VERSION 5.7 ;
  NOWIREEXTENSIONATPIN ON ;
  DIVIDERCHAR "/" ;
  BUSBITCHARS "[]" ;
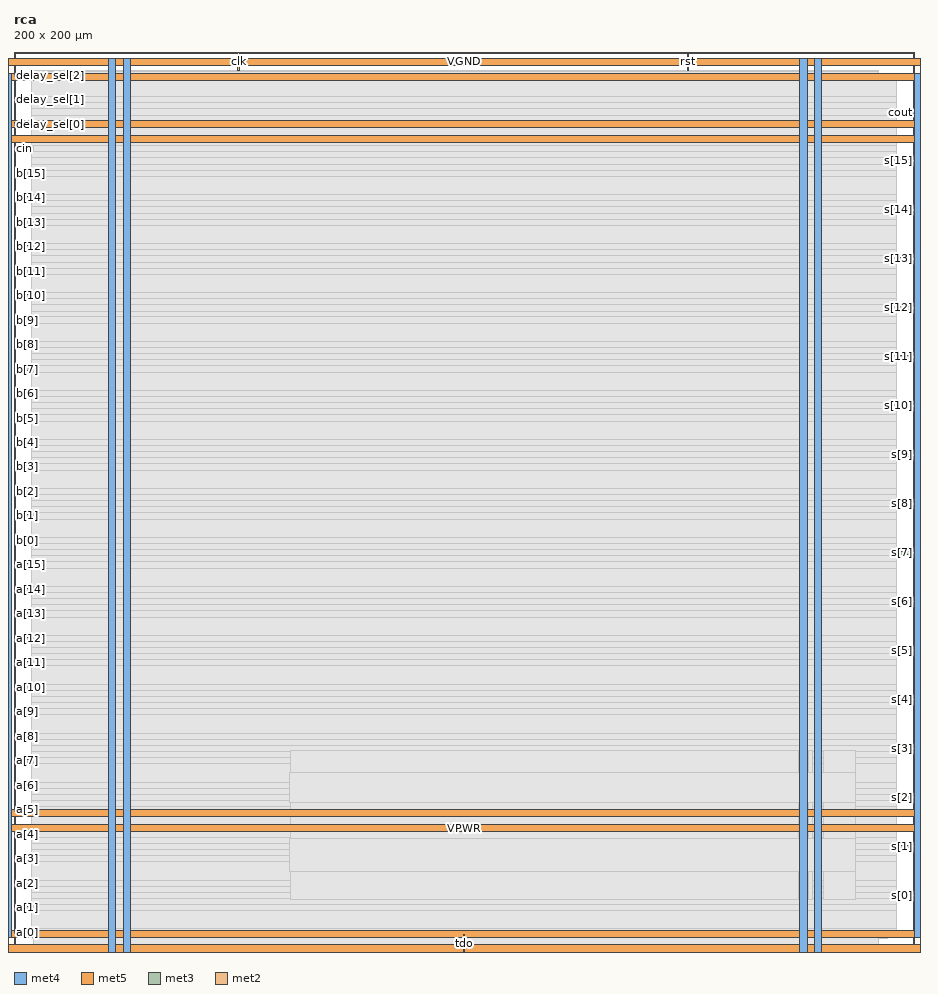
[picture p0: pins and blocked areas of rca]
MACRO rca
  CLASS BLOCK ;
  FOREIGN rca ;
  ORIGIN 0.000 0.000 ;
  SIZE 200.000 BY 200.000 ;
  PIN VGND
    DIRECTION INOUT ;
    USE GROUND ;
    PORT
      LAYER met4 ;
        RECT -5.380 -0.020 -3.780 198.580 ;
    END
    PORT
      LAYER met5 ;
        RECT -5.380 -0.020 205.020 1.580 ;
    END
    PORT
      LAYER met5 ;
        RECT -5.380 196.980 205.020 198.580 ;
    END
    PORT
      LAYER met4 ;
        RECT 203.420 -0.020 205.020 198.580 ;
    END
    PORT
      LAYER met4 ;
        RECT 24.340 -0.020 25.940 198.580 ;
    END
    PORT
      LAYER met4 ;
        RECT 177.940 -0.020 179.540 198.580 ;
    END
    PORT
      LAYER met5 ;
        RECT -5.380 30.030 205.020 31.630 ;
    END
    PORT
      LAYER met5 ;
        RECT -5.380 183.210 205.020 184.810 ;
    END
  END VGND
  PIN VPWR
    DIRECTION INOUT ;
    USE POWER ;
    PORT
      LAYER met4 ;
        RECT -2.080 3.280 -0.480 195.280 ;
    END
    PORT
      LAYER met5 ;
        RECT -2.080 3.280 201.720 4.880 ;
    END
    PORT
      LAYER met5 ;
        RECT -2.080 193.680 201.720 195.280 ;
    END
    PORT
      LAYER met4 ;
        RECT 200.120 3.280 201.720 195.280 ;
    END
    PORT
      LAYER met4 ;
        RECT 21.040 -0.020 22.640 198.580 ;
    END
    PORT
      LAYER met4 ;
        RECT 174.640 -0.020 176.240 198.580 ;
    END
    PORT
      LAYER met5 ;
        RECT -5.380 26.730 205.020 28.330 ;
    END
    PORT
      LAYER met5 ;
        RECT -5.380 179.910 205.020 181.510 ;
    END
  END VPWR
  PIN a[0]
    DIRECTION INPUT ;
    USE SIGNAL ;
    ANTENNAGATEAREA 0.196500 ;
    PORT
      LAYER met3 ;
        RECT 0.000 4.120 4.000 4.720 ;
    END
  END a[0]
  PIN a[10]
    DIRECTION INPUT ;
    USE SIGNAL ;
    ANTENNAGATEAREA 0.196500 ;
    PORT
      LAYER met3 ;
        RECT 0.000 58.520 4.000 59.120 ;
    END
  END a[10]
  PIN a[11]
    DIRECTION INPUT ;
    USE SIGNAL ;
    ANTENNAGATEAREA 0.196500 ;
    PORT
      LAYER met3 ;
        RECT 0.000 63.960 4.000 64.560 ;
    END
  END a[11]
  PIN a[12]
    DIRECTION INPUT ;
    USE SIGNAL ;
    ANTENNAGATEAREA 0.196500 ;
    PORT
      LAYER met3 ;
        RECT 0.000 69.400 4.000 70.000 ;
    END
  END a[12]
  PIN a[13]
    DIRECTION INPUT ;
    USE SIGNAL ;
    ANTENNAGATEAREA 0.196500 ;
    PORT
      LAYER met3 ;
        RECT 0.000 74.840 4.000 75.440 ;
    END
  END a[13]
  PIN a[14]
    DIRECTION INPUT ;
    USE SIGNAL ;
    ANTENNAGATEAREA 0.196500 ;
    PORT
      LAYER met3 ;
        RECT 0.000 80.280 4.000 80.880 ;
    END
  END a[14]
  PIN a[15]
    DIRECTION INPUT ;
    USE SIGNAL ;
    ANTENNAGATEAREA 0.196500 ;
    PORT
      LAYER met3 ;
        RECT 0.000 85.720 4.000 86.320 ;
    END
  END a[15]
  PIN a[1]
    DIRECTION INPUT ;
    USE SIGNAL ;
    ANTENNAGATEAREA 0.196500 ;
    PORT
      LAYER met3 ;
        RECT 0.000 9.560 4.000 10.160 ;
    END
  END a[1]
  PIN a[2]
    DIRECTION INPUT ;
    USE SIGNAL ;
    ANTENNAGATEAREA 0.196500 ;
    PORT
      LAYER met3 ;
        RECT 0.000 15.000 4.000 15.600 ;
    END
  END a[2]
  PIN a[3]
    DIRECTION INPUT ;
    USE SIGNAL ;
    ANTENNAGATEAREA 0.196500 ;
    PORT
      LAYER met3 ;
        RECT 0.000 20.440 4.000 21.040 ;
    END
  END a[3]
  PIN a[4]
    DIRECTION INPUT ;
    USE SIGNAL ;
    ANTENNAGATEAREA 0.196500 ;
    PORT
      LAYER met3 ;
        RECT 0.000 25.880 4.000 26.480 ;
    END
  END a[4]
  PIN a[5]
    DIRECTION INPUT ;
    USE SIGNAL ;
    ANTENNAGATEAREA 0.196500 ;
    PORT
      LAYER met3 ;
        RECT 0.000 31.320 4.000 31.920 ;
    END
  END a[5]
  PIN a[6]
    DIRECTION INPUT ;
    USE SIGNAL ;
    ANTENNAGATEAREA 0.196500 ;
    PORT
      LAYER met3 ;
        RECT 0.000 36.760 4.000 37.360 ;
    END
  END a[6]
  PIN a[7]
    DIRECTION INPUT ;
    USE SIGNAL ;
    ANTENNAGATEAREA 0.196500 ;
    PORT
      LAYER met3 ;
        RECT 0.000 42.200 4.000 42.800 ;
    END
  END a[7]
  PIN a[8]
    DIRECTION INPUT ;
    USE SIGNAL ;
    ANTENNAGATEAREA 0.196500 ;
    PORT
      LAYER met3 ;
        RECT 0.000 47.640 4.000 48.240 ;
    END
  END a[8]
  PIN a[9]
    DIRECTION INPUT ;
    USE SIGNAL ;
    ANTENNAGATEAREA 0.196500 ;
    PORT
      LAYER met3 ;
        RECT 0.000 53.080 4.000 53.680 ;
    END
  END a[9]
  PIN b[0]
    DIRECTION INPUT ;
    USE SIGNAL ;
    ANTENNAGATEAREA 0.196500 ;
    PORT
      LAYER met3 ;
        RECT 0.000 91.160 4.000 91.760 ;
    END
  END b[0]
  PIN b[10]
    DIRECTION INPUT ;
    USE SIGNAL ;
    ANTENNAGATEAREA 0.196500 ;
    PORT
      LAYER met3 ;
        RECT 0.000 145.560 4.000 146.160 ;
    END
  END b[10]
  PIN b[11]
    DIRECTION INPUT ;
    USE SIGNAL ;
    ANTENNAGATEAREA 0.196500 ;
    PORT
      LAYER met3 ;
        RECT 0.000 151.000 4.000 151.600 ;
    END
  END b[11]
  PIN b[12]
    DIRECTION INPUT ;
    USE SIGNAL ;
    ANTENNAGATEAREA 0.196500 ;
    PORT
      LAYER met3 ;
        RECT 0.000 156.440 4.000 157.040 ;
    END
  END b[12]
  PIN b[13]
    DIRECTION INPUT ;
    USE SIGNAL ;
    ANTENNAGATEAREA 0.196500 ;
    PORT
      LAYER met3 ;
        RECT 0.000 161.880 4.000 162.480 ;
    END
  END b[13]
  PIN b[14]
    DIRECTION INPUT ;
    USE SIGNAL ;
    ANTENNAGATEAREA 0.196500 ;
    PORT
      LAYER met3 ;
        RECT 0.000 167.320 4.000 167.920 ;
    END
  END b[14]
  PIN b[15]
    DIRECTION INPUT ;
    USE SIGNAL ;
    ANTENNAGATEAREA 0.196500 ;
    PORT
      LAYER met3 ;
        RECT 0.000 172.760 4.000 173.360 ;
    END
  END b[15]
  PIN b[1]
    DIRECTION INPUT ;
    USE SIGNAL ;
    ANTENNAGATEAREA 0.196500 ;
    PORT
      LAYER met3 ;
        RECT 0.000 96.600 4.000 97.200 ;
    END
  END b[1]
  PIN b[2]
    DIRECTION INPUT ;
    USE SIGNAL ;
    ANTENNAGATEAREA 0.196500 ;
    PORT
      LAYER met3 ;
        RECT 0.000 102.040 4.000 102.640 ;
    END
  END b[2]
  PIN b[3]
    DIRECTION INPUT ;
    USE SIGNAL ;
    ANTENNAGATEAREA 0.196500 ;
    PORT
      LAYER met3 ;
        RECT 0.000 107.480 4.000 108.080 ;
    END
  END b[3]
  PIN b[4]
    DIRECTION INPUT ;
    USE SIGNAL ;
    ANTENNAGATEAREA 0.196500 ;
    PORT
      LAYER met3 ;
        RECT 0.000 112.920 4.000 113.520 ;
    END
  END b[4]
  PIN b[5]
    DIRECTION INPUT ;
    USE SIGNAL ;
    ANTENNAGATEAREA 0.196500 ;
    PORT
      LAYER met3 ;
        RECT 0.000 118.360 4.000 118.960 ;
    END
  END b[5]
  PIN b[6]
    DIRECTION INPUT ;
    USE SIGNAL ;
    ANTENNAGATEAREA 0.196500 ;
    PORT
      LAYER met3 ;
        RECT 0.000 123.800 4.000 124.400 ;
    END
  END b[6]
  PIN b[7]
    DIRECTION INPUT ;
    USE SIGNAL ;
    ANTENNAGATEAREA 0.196500 ;
    PORT
      LAYER met3 ;
        RECT 0.000 129.240 4.000 129.840 ;
    END
  END b[7]
  PIN b[8]
    DIRECTION INPUT ;
    USE SIGNAL ;
    ANTENNAGATEAREA 0.196500 ;
    PORT
      LAYER met3 ;
        RECT 0.000 134.680 4.000 135.280 ;
    END
  END b[8]
  PIN b[9]
    DIRECTION INPUT ;
    USE SIGNAL ;
    ANTENNAGATEAREA 0.196500 ;
    PORT
      LAYER met3 ;
        RECT 0.000 140.120 4.000 140.720 ;
    END
  END b[9]
  PIN cin
    DIRECTION INPUT ;
    USE SIGNAL ;
    ANTENNAGATEAREA 0.196500 ;
    PORT
      LAYER met3 ;
        RECT 0.000 178.200 4.000 178.800 ;
    END
  END cin
  PIN clk
    DIRECTION INPUT ;
    USE SIGNAL ;
    ANTENNAGATEAREA 1.704000 ;
    PORT
      LAYER met2 ;
        RECT 49.770 196.000 50.050 200.000 ;
    END
  END clk
  PIN cout
    DIRECTION OUTPUT ;
    USE SIGNAL ;
    ANTENNADIFFAREA 0.445500 ;
    PORT
      LAYER met3 ;
        RECT 196.000 186.360 200.000 186.960 ;
    END
  END cout
  PIN delay_sel[0]
    DIRECTION INPUT ;
    USE SIGNAL ;
    ANTENNAGATEAREA 0.159000 ;
    PORT
      LAYER met3 ;
        RECT 0.000 183.640 4.000 184.240 ;
    END
  END delay_sel[0]
  PIN delay_sel[1]
    DIRECTION INPUT ;
    USE SIGNAL ;
    ANTENNAGATEAREA 0.159000 ;
    PORT
      LAYER met3 ;
        RECT 0.000 189.080 4.000 189.680 ;
    END
  END delay_sel[1]
  PIN delay_sel[2]
    DIRECTION INPUT ;
    USE SIGNAL ;
    ANTENNAGATEAREA 0.213000 ;
    PORT
      LAYER met3 ;
        RECT 0.000 194.520 4.000 195.120 ;
    END
  END delay_sel[2]
  PIN rst
    DIRECTION INPUT ;
    USE SIGNAL ;
    ANTENNAGATEAREA 0.196500 ;
    PORT
      LAYER met2 ;
        RECT 149.590 196.000 149.870 200.000 ;
    END
  END rst
  PIN s[0]
    DIRECTION OUTPUT ;
    USE SIGNAL ;
    ANTENNADIFFAREA 0.445500 ;
    PORT
      LAYER met3 ;
        RECT 196.000 12.280 200.000 12.880 ;
    END
  END s[0]
  PIN s[10]
    DIRECTION OUTPUT ;
    USE SIGNAL ;
    ANTENNADIFFAREA 0.445500 ;
    PORT
      LAYER met3 ;
        RECT 196.000 121.080 200.000 121.680 ;
    END
  END s[10]
  PIN s[11]
    DIRECTION OUTPUT ;
    USE SIGNAL ;
    ANTENNADIFFAREA 0.445500 ;
    PORT
      LAYER met3 ;
        RECT 196.000 131.960 200.000 132.560 ;
    END
  END s[11]
  PIN s[12]
    DIRECTION OUTPUT ;
    USE SIGNAL ;
    ANTENNADIFFAREA 0.445500 ;
    PORT
      LAYER met3 ;
        RECT 196.000 142.840 200.000 143.440 ;
    END
  END s[12]
  PIN s[13]
    DIRECTION OUTPUT ;
    USE SIGNAL ;
    ANTENNADIFFAREA 0.445500 ;
    PORT
      LAYER met3 ;
        RECT 196.000 153.720 200.000 154.320 ;
    END
  END s[13]
  PIN s[14]
    DIRECTION OUTPUT ;
    USE SIGNAL ;
    ANTENNADIFFAREA 0.445500 ;
    PORT
      LAYER met3 ;
        RECT 196.000 164.600 200.000 165.200 ;
    END
  END s[14]
  PIN s[15]
    DIRECTION OUTPUT ;
    USE SIGNAL ;
    ANTENNADIFFAREA 0.445500 ;
    PORT
      LAYER met3 ;
        RECT 196.000 175.480 200.000 176.080 ;
    END
  END s[15]
  PIN s[1]
    DIRECTION OUTPUT ;
    USE SIGNAL ;
    ANTENNADIFFAREA 0.445500 ;
    PORT
      LAYER met3 ;
        RECT 196.000 23.160 200.000 23.760 ;
    END
  END s[1]
  PIN s[2]
    DIRECTION OUTPUT ;
    USE SIGNAL ;
    ANTENNADIFFAREA 0.445500 ;
    PORT
      LAYER met3 ;
        RECT 196.000 34.040 200.000 34.640 ;
    END
  END s[2]
  PIN s[3]
    DIRECTION OUTPUT ;
    USE SIGNAL ;
    ANTENNADIFFAREA 0.445500 ;
    PORT
      LAYER met3 ;
        RECT 196.000 44.920 200.000 45.520 ;
    END
  END s[3]
  PIN s[4]
    DIRECTION OUTPUT ;
    USE SIGNAL ;
    ANTENNADIFFAREA 0.445500 ;
    PORT
      LAYER met3 ;
        RECT 196.000 55.800 200.000 56.400 ;
    END
  END s[4]
  PIN s[5]
    DIRECTION OUTPUT ;
    USE SIGNAL ;
    ANTENNADIFFAREA 0.445500 ;
    PORT
      LAYER met3 ;
        RECT 196.000 66.680 200.000 67.280 ;
    END
  END s[5]
  PIN s[6]
    DIRECTION OUTPUT ;
    USE SIGNAL ;
    ANTENNADIFFAREA 0.445500 ;
    PORT
      LAYER met3 ;
        RECT 196.000 77.560 200.000 78.160 ;
    END
  END s[6]
  PIN s[7]
    DIRECTION OUTPUT ;
    USE SIGNAL ;
    ANTENNADIFFAREA 0.445500 ;
    PORT
      LAYER met3 ;
        RECT 196.000 88.440 200.000 89.040 ;
    END
  END s[7]
  PIN s[8]
    DIRECTION OUTPUT ;
    USE SIGNAL ;
    ANTENNADIFFAREA 0.445500 ;
    PORT
      LAYER met3 ;
        RECT 196.000 99.320 200.000 99.920 ;
    END
  END s[8]
  PIN s[9]
    DIRECTION OUTPUT ;
    USE SIGNAL ;
    ANTENNADIFFAREA 0.445500 ;
    PORT
      LAYER met3 ;
        RECT 196.000 110.200 200.000 110.800 ;
    END
  END s[9]
  PIN tdo
    DIRECTION OUTPUT ;
    USE SIGNAL ;
    ANTENNADIFFAREA 0.445500 ;
    PORT
      LAYER met2 ;
        RECT 99.910 0.000 100.190 4.000 ;
    END
  END tdo
  OBS
      LAYER nwell ;
        RECT 5.330 10.795 194.310 187.870 ;
      LAYER li1 ;
        RECT 5.520 10.795 194.120 187.765 ;
      LAYER met1 ;
        RECT 4.210 3.100 194.120 187.920 ;
      LAYER met2 ;
        RECT 4.230 195.720 49.490 196.000 ;
        RECT 50.330 195.720 149.310 196.000 ;
        RECT 150.150 195.720 192.190 196.000 ;
        RECT 4.230 4.280 192.190 195.720 ;
        RECT 4.230 1.000 99.630 4.280 ;
        RECT 100.470 1.000 192.190 4.280 ;
      LAYER met3 ;
        RECT 4.400 194.120 196.000 194.985 ;
        RECT 3.990 190.080 196.000 194.120 ;
        RECT 4.400 188.680 196.000 190.080 ;
        RECT 3.990 187.360 196.000 188.680 ;
        RECT 3.990 185.960 195.600 187.360 ;
        RECT 3.990 184.640 196.000 185.960 ;
        RECT 4.400 183.240 196.000 184.640 ;
        RECT 3.990 179.200 196.000 183.240 ;
        RECT 4.400 177.800 196.000 179.200 ;
        RECT 3.990 176.480 196.000 177.800 ;
        RECT 3.990 175.080 195.600 176.480 ;
        RECT 3.990 173.760 196.000 175.080 ;
        RECT 4.400 172.360 196.000 173.760 ;
        RECT 3.990 168.320 196.000 172.360 ;
        RECT 4.400 166.920 196.000 168.320 ;
        RECT 3.990 165.600 196.000 166.920 ;
        RECT 3.990 164.200 195.600 165.600 ;
        RECT 3.990 162.880 196.000 164.200 ;
        RECT 4.400 161.480 196.000 162.880 ;
        RECT 3.990 157.440 196.000 161.480 ;
        RECT 4.400 156.040 196.000 157.440 ;
        RECT 3.990 154.720 196.000 156.040 ;
        RECT 3.990 153.320 195.600 154.720 ;
        RECT 3.990 152.000 196.000 153.320 ;
        RECT 4.400 150.600 196.000 152.000 ;
        RECT 3.990 146.560 196.000 150.600 ;
        RECT 4.400 145.160 196.000 146.560 ;
        RECT 3.990 143.840 196.000 145.160 ;
        RECT 3.990 142.440 195.600 143.840 ;
        RECT 3.990 141.120 196.000 142.440 ;
        RECT 4.400 139.720 196.000 141.120 ;
        RECT 3.990 135.680 196.000 139.720 ;
        RECT 4.400 134.280 196.000 135.680 ;
        RECT 3.990 132.960 196.000 134.280 ;
        RECT 3.990 131.560 195.600 132.960 ;
        RECT 3.990 130.240 196.000 131.560 ;
        RECT 4.400 128.840 196.000 130.240 ;
        RECT 3.990 124.800 196.000 128.840 ;
        RECT 4.400 123.400 196.000 124.800 ;
        RECT 3.990 122.080 196.000 123.400 ;
        RECT 3.990 120.680 195.600 122.080 ;
        RECT 3.990 119.360 196.000 120.680 ;
        RECT 4.400 117.960 196.000 119.360 ;
        RECT 3.990 113.920 196.000 117.960 ;
        RECT 4.400 112.520 196.000 113.920 ;
        RECT 3.990 111.200 196.000 112.520 ;
        RECT 3.990 109.800 195.600 111.200 ;
        RECT 3.990 108.480 196.000 109.800 ;
        RECT 4.400 107.080 196.000 108.480 ;
        RECT 3.990 103.040 196.000 107.080 ;
        RECT 4.400 101.640 196.000 103.040 ;
        RECT 3.990 100.320 196.000 101.640 ;
        RECT 3.990 98.920 195.600 100.320 ;
        RECT 3.990 97.600 196.000 98.920 ;
        RECT 4.400 96.200 196.000 97.600 ;
        RECT 3.990 92.160 196.000 96.200 ;
        RECT 4.400 90.760 196.000 92.160 ;
        RECT 3.990 89.440 196.000 90.760 ;
        RECT 3.990 88.040 195.600 89.440 ;
        RECT 3.990 86.720 196.000 88.040 ;
        RECT 4.400 85.320 196.000 86.720 ;
        RECT 3.990 81.280 196.000 85.320 ;
        RECT 4.400 79.880 196.000 81.280 ;
        RECT 3.990 78.560 196.000 79.880 ;
        RECT 3.990 77.160 195.600 78.560 ;
        RECT 3.990 75.840 196.000 77.160 ;
        RECT 4.400 74.440 196.000 75.840 ;
        RECT 3.990 70.400 196.000 74.440 ;
        RECT 4.400 69.000 196.000 70.400 ;
        RECT 3.990 67.680 196.000 69.000 ;
        RECT 3.990 66.280 195.600 67.680 ;
        RECT 3.990 64.960 196.000 66.280 ;
        RECT 4.400 63.560 196.000 64.960 ;
        RECT 3.990 59.520 196.000 63.560 ;
        RECT 4.400 58.120 196.000 59.520 ;
        RECT 3.990 56.800 196.000 58.120 ;
        RECT 3.990 55.400 195.600 56.800 ;
        RECT 3.990 54.080 196.000 55.400 ;
        RECT 4.400 52.680 196.000 54.080 ;
        RECT 3.990 48.640 196.000 52.680 ;
        RECT 4.400 47.240 196.000 48.640 ;
        RECT 3.990 45.920 196.000 47.240 ;
        RECT 3.990 44.520 195.600 45.920 ;
        RECT 3.990 43.200 196.000 44.520 ;
        RECT 4.400 41.800 196.000 43.200 ;
        RECT 3.990 37.760 196.000 41.800 ;
        RECT 4.400 36.360 196.000 37.760 ;
        RECT 3.990 35.040 196.000 36.360 ;
        RECT 3.990 33.640 195.600 35.040 ;
        RECT 3.990 32.320 196.000 33.640 ;
        RECT 4.400 30.920 196.000 32.320 ;
        RECT 3.990 26.880 196.000 30.920 ;
        RECT 4.400 25.480 196.000 26.880 ;
        RECT 3.990 24.160 196.000 25.480 ;
        RECT 3.990 22.760 195.600 24.160 ;
        RECT 3.990 21.440 196.000 22.760 ;
        RECT 4.400 20.040 196.000 21.440 ;
        RECT 3.990 16.000 196.000 20.040 ;
        RECT 4.400 14.600 196.000 16.000 ;
        RECT 3.990 13.280 196.000 14.600 ;
        RECT 3.990 11.880 195.600 13.280 ;
        RECT 3.990 10.560 196.000 11.880 ;
        RECT 4.400 9.160 196.000 10.560 ;
        RECT 3.990 5.120 196.000 9.160 ;
        RECT 4.400 3.760 196.000 5.120 ;
      LAYER met4 ;
        RECT 61.510 11.640 174.240 44.760 ;
        RECT 176.640 11.640 177.540 44.760 ;
        RECT 179.940 11.640 186.890 44.760 ;
      LAYER met5 ;
        RECT 61.300 33.230 187.100 39.900 ;
        RECT 61.300 17.900 187.100 25.130 ;
  END
END rca
END LIBRARY

